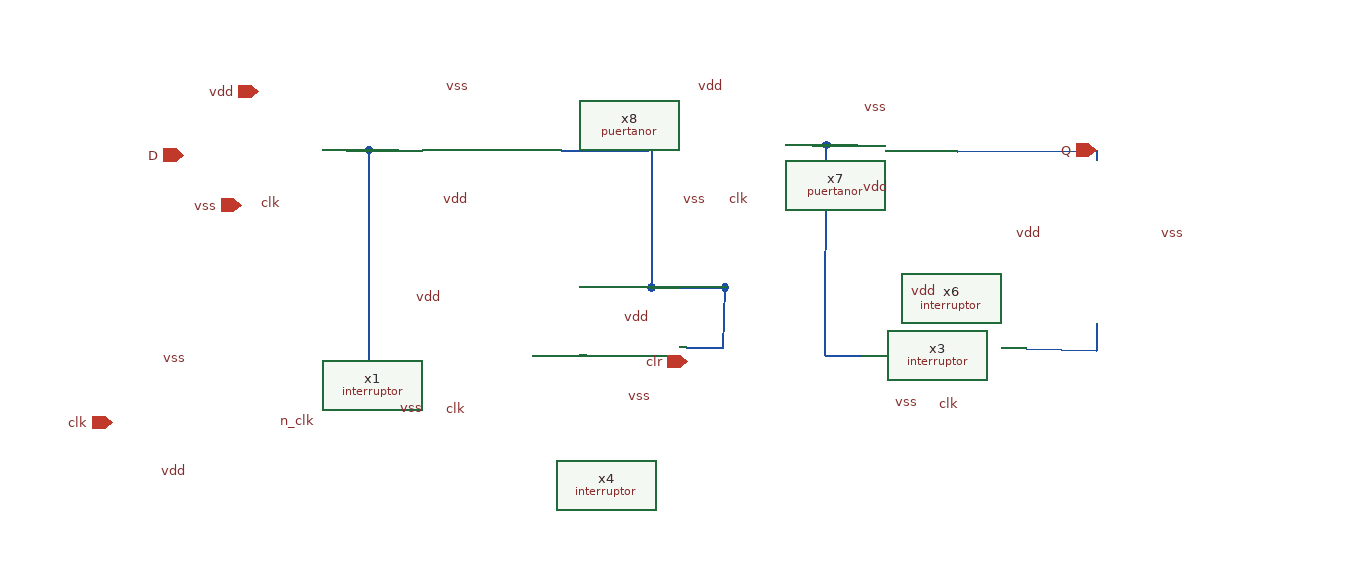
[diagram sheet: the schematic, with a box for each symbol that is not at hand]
v {xschem version=3.4.8RC file_version=1.3}
G {}
K {}
V {}
S {}
F {}
E {}
N -202 -164 -178 -164 {lab=#net1}
N -48 -164 22 -164 {lab=#net2}
N -202 -164 -202 4 {lab=#net1}
N -220 -164 -202 -164 {lab=#net1}
N -71 0 -28 -0 {lab=#net3}
N 52 -6 82 -6 {lab=#net4}
N 82 -6 83 -54 {lab=#net4}
N 83 -54 84 -54 {lab=#net4}
N 24 -164 24 -54 {lab=#net4}
N 23 -54 24 -54 {lab=#net4}
N 24 -54 83 -54 {lab=#net4}
N 164 -168 189 -168 {lab=#net5}
N 269 -163 380 -164 {lab=xxx}
N 380 -164 380 -156 {lab=xxx}
N 380 -25 380 -4 {lab=#net6}
N 324 -5 380 -4 {lab=#net6}
N 163 0 164 -168 {lab=#net5}
N 153 -168 164 -168 {lab=#net5}
N 163 0 193 0 {lab=#net5}
C {blocks/interruptor/interruptor.sym} -160 -60 0 0 {name=x1}
C {blocks/inversor/untitled.sym} -30 -164 2 0 {name=x2}
C {blocks/interruptor/interruptor.sym} 214 -64 0 0 {name=x3}
C {blocks/interruptor/interruptor.sym} -12 104 0 0 {name=x4}
C {blocks/inversor/untitled.sym} -256 54 2 0 {name=x5}
C {blocks/interruptor/interruptor.sym} 384 100 0 0 {name=x6}
C {blocks/puertanor/puertanor.sym} 249 -194 2 0 {name=x7}
C {blocks/puertanor/puertanor.sym} -8 31 0 0 {name=x8}
C {blocks/inversor/untitled.sym} 379 -6 3 0 {name=x9}
C {iopin.sym} -350 -160 2 0 {name=p1 lab=D
}
C {lab_pin.sym} -270 -120 3 0 {name=p2 sig_type=std_logic lab=clk}
C {iopin.sym} -290 -211 3 0 {name=p3 lab=vdd}
C {iopin.sym} -304 -120 1 0 {name=p4 lab=vss}
C {iopin.sym} -407 54 2 0 {name=p5 lab=clk

}
C {lab_pin.sym} -276 54 2 0 {name=p6 sig_type=std_logic lab=n_clk
}
C {lab_pin.sym} -346 94 3 0 {name=p7 sig_type=std_logic lab=vdd}
C {lab_pin.sym} -346 4 1 0 {name=p8 sig_type=std_logic lab=vss}
C {lab_pin.sym} -122 45 3 0 {name=p9 sig_type=std_logic lab=clk}
C {lab_pin.sym} -156 44 3 0 {name=p10 sig_type=std_logic lab=vss
}
C {lab_pin.sym} -142 -45 1 0 {name=p11 sig_type=std_logic lab=vdd}
C {lab_pin.sym} -120 -123 3 0 {name=p12 sig_type=std_logic lab=vdd
}
C {lab_pin.sym} -119 -214 1 0 {name=p13 sig_type=std_logic lab=vss}
C {lab_pin.sym} 70 -123 3 0 {name=p14 sig_type=std_logic lab=vss}
C {lab_pin.sym} 105 -123 3 0 {name=p15 sig_type=std_logic lab=clk}
C {lab_pin.sym} 84 -214 1 0 {name=p16 sig_type=std_logic lab=vdd}
C {lab_pin.sym} 216 -133 3 0 {name=p17 sig_type=std_logic lab=vdd}
C {lab_pin.sym} 215 -197 1 0 {name=p18 sig_type=std_logic lab=vss}
C {lab_pin.sym} 338 -96 0 0 {name=p19 sig_type=std_logic lab=vdd}
C {lab_pin.sym} 429 -96 2 0 {name=p20 sig_type=std_logic lab=vss}
C {lab_pin.sym} 273 41 3 0 {name=p21 sig_type=std_logic lab=clk}
C {lab_pin.sym} 240 39 3 0 {name=p22 sig_type=std_logic lab=vss}
C {lab_pin.sym} 254 -50 1 0 {name=p23 sig_type=std_logic lab=vdd}
C {lab_pin.sym} 26 34 3 0 {name=p24 sig_type=std_logic lab=vss}
C {lab_pin.sym} 25 -29 1 0 {name=p25 sig_type=std_logic lab=vdd}
C {iopin.sym} 53 5 0 0 {name=p26 lab=clr
}
C {iopin.sym} 380 -164 0 0 {name=p27 lab=Q}
